VERSION 5.7 ;
  NOWIREEXTENSIONATPIN ON ;
  DIVIDERCHAR "/" ;
  BUSBITCHARS "[]" ;
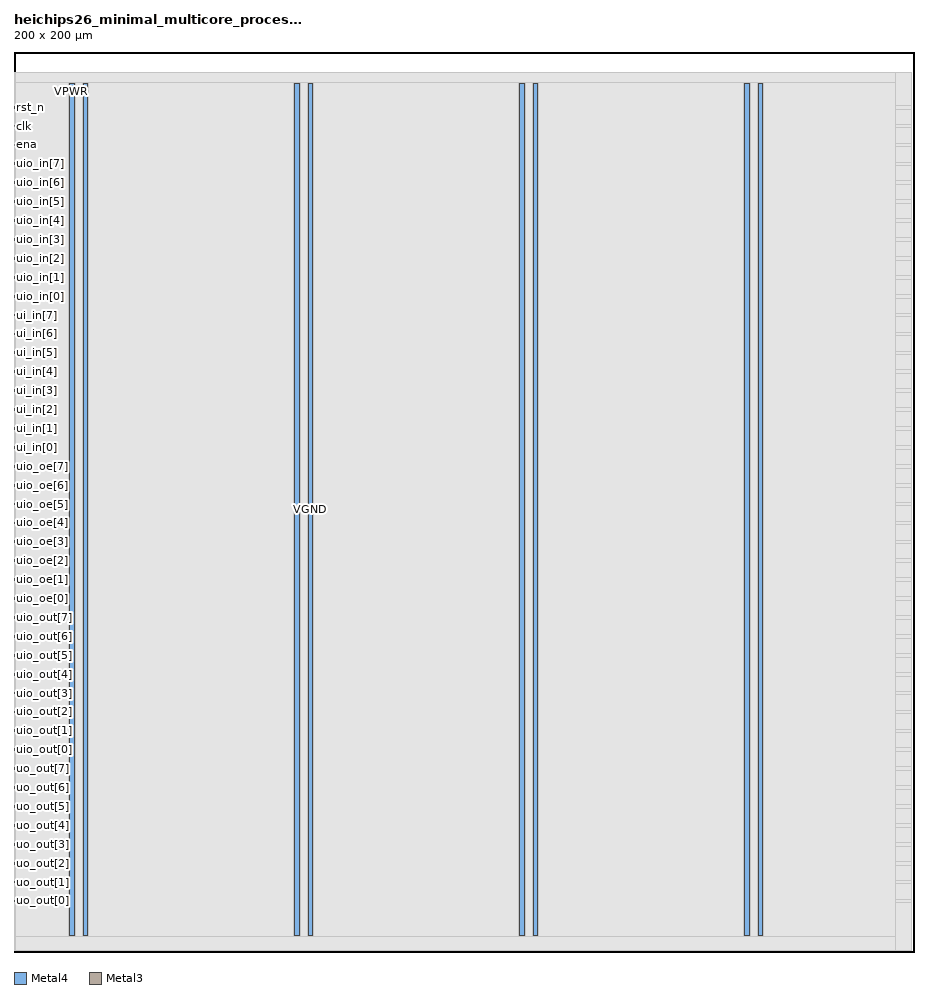
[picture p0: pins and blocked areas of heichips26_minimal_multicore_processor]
MACRO heichips26_minimal_multicore_processor
  CLASS BLOCK ;
  FOREIGN heichips26_minimal_multicore_processor ;
  ORIGIN 0.000 0.000 ;
  SIZE 200.000 BY 200.000 ;
  PIN VGND
    DIRECTION INOUT ;
    USE GROUND ;
    PORT
      LAYER Metal4 ;
        RECT 15.380 3.560 16.380 193.000 ;
    END
    PORT
      LAYER Metal4 ;
        RECT 65.380 3.560 66.380 193.000 ;
    END
    PORT
      LAYER Metal4 ;
        RECT 115.380 3.560 116.380 193.000 ;
    END
    PORT
      LAYER Metal4 ;
        RECT 165.380 3.560 166.380 193.000 ;
    END
  END VGND
  PIN VPWR
    DIRECTION INOUT ;
    USE POWER ;
    PORT
      LAYER Metal4 ;
        RECT 12.380 3.560 13.380 193.000 ;
    END
    PORT
      LAYER Metal4 ;
        RECT 62.380 3.560 63.380 193.000 ;
    END
    PORT
      LAYER Metal4 ;
        RECT 112.380 3.560 113.380 193.000 ;
    END
    PORT
      LAYER Metal4 ;
        RECT 162.380 3.560 163.380 193.000 ;
    END
  END VPWR
  PIN clk
    DIRECTION INPUT ;
    USE SIGNAL ;
    ANTENNAGATEAREA 0.725400 ;
    PORT
      LAYER Metal3 ;
        RECT 0.000 183.340 0.400 183.740 ;
    END
  END clk
  PIN ena
    DIRECTION INPUT ;
    USE SIGNAL ;
    PORT
      LAYER Metal3 ;
        RECT 0.000 179.140 0.400 179.540 ;
    END
  END ena
  PIN rst_n
    DIRECTION INPUT ;
    USE SIGNAL ;
    ANTENNAGATEAREA 0.180700 ;
    PORT
      LAYER Metal3 ;
        RECT 0.000 187.540 0.400 187.940 ;
    END
  END rst_n
  PIN ui_in[0]
    DIRECTION INPUT ;
    USE SIGNAL ;
    ANTENNAGATEAREA 0.180700 ;
    PORT
      LAYER Metal3 ;
        RECT 0.000 111.940 0.400 112.340 ;
    END
  END ui_in[0]
  PIN ui_in[1]
    DIRECTION INPUT ;
    USE SIGNAL ;
    ANTENNAGATEAREA 0.180700 ;
    PORT
      LAYER Metal3 ;
        RECT 0.000 116.140 0.400 116.540 ;
    END
  END ui_in[1]
  PIN ui_in[2]
    DIRECTION INPUT ;
    USE SIGNAL ;
    ANTENNAGATEAREA 0.180700 ;
    PORT
      LAYER Metal3 ;
        RECT 0.000 120.340 0.400 120.740 ;
    END
  END ui_in[2]
  PIN ui_in[3]
    DIRECTION INPUT ;
    USE SIGNAL ;
    ANTENNAGATEAREA 0.180700 ;
    PORT
      LAYER Metal3 ;
        RECT 0.000 124.540 0.400 124.940 ;
    END
  END ui_in[3]
  PIN ui_in[4]
    DIRECTION INPUT ;
    USE SIGNAL ;
    ANTENNAGATEAREA 0.180700 ;
    PORT
      LAYER Metal3 ;
        RECT 0.000 128.740 0.400 129.140 ;
    END
  END ui_in[4]
  PIN ui_in[5]
    DIRECTION INPUT ;
    USE SIGNAL ;
    ANTENNAGATEAREA 0.180700 ;
    PORT
      LAYER Metal3 ;
        RECT 0.000 132.940 0.400 133.340 ;
    END
  END ui_in[5]
  PIN ui_in[6]
    DIRECTION INPUT ;
    USE SIGNAL ;
    ANTENNAGATEAREA 0.180700 ;
    PORT
      LAYER Metal3 ;
        RECT 0.000 137.140 0.400 137.540 ;
    END
  END ui_in[6]
  PIN ui_in[7]
    DIRECTION INPUT ;
    USE SIGNAL ;
    ANTENNAGATEAREA 0.180700 ;
    PORT
      LAYER Metal3 ;
        RECT 0.000 141.340 0.400 141.740 ;
    END
  END ui_in[7]
  PIN uio_in[0]
    DIRECTION INPUT ;
    USE SIGNAL ;
    ANTENNAGATEAREA 0.180700 ;
    PORT
      LAYER Metal3 ;
        RECT 0.000 145.540 0.400 145.940 ;
    END
  END uio_in[0]
  PIN uio_in[1]
    DIRECTION INPUT ;
    USE SIGNAL ;
    ANTENNAGATEAREA 0.180700 ;
    PORT
      LAYER Metal3 ;
        RECT 0.000 149.740 0.400 150.140 ;
    END
  END uio_in[1]
  PIN uio_in[2]
    DIRECTION INPUT ;
    USE SIGNAL ;
    ANTENNAGATEAREA 0.180700 ;
    PORT
      LAYER Metal3 ;
        RECT 0.000 153.940 0.400 154.340 ;
    END
  END uio_in[2]
  PIN uio_in[3]
    DIRECTION INPUT ;
    USE SIGNAL ;
    ANTENNAGATEAREA 0.180700 ;
    PORT
      LAYER Metal3 ;
        RECT 0.000 158.140 0.400 158.540 ;
    END
  END uio_in[3]
  PIN uio_in[4]
    DIRECTION INPUT ;
    USE SIGNAL ;
    ANTENNAGATEAREA 0.180700 ;
    PORT
      LAYER Metal3 ;
        RECT 0.000 162.340 0.400 162.740 ;
    END
  END uio_in[4]
  PIN uio_in[5]
    DIRECTION INPUT ;
    USE SIGNAL ;
    ANTENNAGATEAREA 0.180700 ;
    PORT
      LAYER Metal3 ;
        RECT 0.000 166.540 0.400 166.940 ;
    END
  END uio_in[5]
  PIN uio_in[6]
    DIRECTION INPUT ;
    USE SIGNAL ;
    ANTENNAGATEAREA 0.180700 ;
    ANTENNADIFFAREA 2.015400 ;
    PORT
      LAYER Metal3 ;
        RECT 0.000 170.740 0.400 171.140 ;
    END
  END uio_in[6]
  PIN uio_in[7]
    DIRECTION INPUT ;
    USE SIGNAL ;
    ANTENNAGATEAREA 0.180700 ;
    ANTENNADIFFAREA 2.015400 ;
    PORT
      LAYER Metal3 ;
        RECT 0.000 174.940 0.400 175.340 ;
    END
  END uio_in[7]
  PIN uio_oe[0]
    DIRECTION OUTPUT ;
    USE SIGNAL ;
    ANTENNADIFFAREA 0.299200 ;
    PORT
      LAYER Metal3 ;
        RECT 0.000 78.340 0.400 78.740 ;
    END
  END uio_oe[0]
  PIN uio_oe[1]
    DIRECTION OUTPUT ;
    USE SIGNAL ;
    ANTENNADIFFAREA 0.299200 ;
    PORT
      LAYER Metal3 ;
        RECT 0.000 82.540 0.400 82.940 ;
    END
  END uio_oe[1]
  PIN uio_oe[2]
    DIRECTION OUTPUT ;
    USE SIGNAL ;
    ANTENNADIFFAREA 0.299200 ;
    PORT
      LAYER Metal3 ;
        RECT 0.000 86.740 0.400 87.140 ;
    END
  END uio_oe[2]
  PIN uio_oe[3]
    DIRECTION OUTPUT ;
    USE SIGNAL ;
    ANTENNADIFFAREA 0.299200 ;
    PORT
      LAYER Metal3 ;
        RECT 0.000 90.940 0.400 91.340 ;
    END
  END uio_oe[3]
  PIN uio_oe[4]
    DIRECTION OUTPUT ;
    USE SIGNAL ;
    ANTENNADIFFAREA 0.299200 ;
    PORT
      LAYER Metal3 ;
        RECT 0.000 95.140 0.400 95.540 ;
    END
  END uio_oe[4]
  PIN uio_oe[5]
    DIRECTION OUTPUT ;
    USE SIGNAL ;
    ANTENNADIFFAREA 0.299200 ;
    PORT
      LAYER Metal3 ;
        RECT 0.000 99.340 0.400 99.740 ;
    END
  END uio_oe[5]
  PIN uio_oe[6]
    DIRECTION OUTPUT ;
    USE SIGNAL ;
    ANTENNADIFFAREA 0.299200 ;
    PORT
      LAYER Metal3 ;
        RECT 0.000 103.540 0.400 103.940 ;
    END
  END uio_oe[6]
  PIN uio_oe[7]
    DIRECTION OUTPUT ;
    USE SIGNAL ;
    ANTENNADIFFAREA 0.299200 ;
    PORT
      LAYER Metal3 ;
        RECT 0.000 107.740 0.400 108.140 ;
    END
  END uio_oe[7]
  PIN uio_out[0]
    DIRECTION OUTPUT ;
    USE SIGNAL ;
    ANTENNADIFFAREA 0.299200 ;
    PORT
      LAYER Metal3 ;
        RECT 0.000 44.740 0.400 45.140 ;
    END
  END uio_out[0]
  PIN uio_out[1]
    DIRECTION OUTPUT ;
    USE SIGNAL ;
    ANTENNADIFFAREA 0.299200 ;
    PORT
      LAYER Metal3 ;
        RECT 0.000 48.940 0.400 49.340 ;
    END
  END uio_out[1]
  PIN uio_out[2]
    DIRECTION OUTPUT ;
    USE SIGNAL ;
    ANTENNADIFFAREA 0.299200 ;
    PORT
      LAYER Metal3 ;
        RECT 0.000 53.140 0.400 53.540 ;
    END
  END uio_out[2]
  PIN uio_out[3]
    DIRECTION OUTPUT ;
    USE SIGNAL ;
    ANTENNADIFFAREA 0.299200 ;
    PORT
      LAYER Metal3 ;
        RECT 0.000 57.340 0.400 57.740 ;
    END
  END uio_out[3]
  PIN uio_out[4]
    DIRECTION OUTPUT ;
    USE SIGNAL ;
    ANTENNADIFFAREA 0.299200 ;
    PORT
      LAYER Metal3 ;
        RECT 0.000 61.540 0.400 61.940 ;
    END
  END uio_out[4]
  PIN uio_out[5]
    DIRECTION OUTPUT ;
    USE SIGNAL ;
    ANTENNADIFFAREA 0.299200 ;
    PORT
      LAYER Metal3 ;
        RECT 0.000 65.740 0.400 66.140 ;
    END
  END uio_out[5]
  PIN uio_out[6]
    DIRECTION OUTPUT ;
    USE SIGNAL ;
    ANTENNADIFFAREA 0.299200 ;
    PORT
      LAYER Metal3 ;
        RECT 0.000 69.940 0.400 70.340 ;
    END
  END uio_out[6]
  PIN uio_out[7]
    DIRECTION OUTPUT ;
    USE SIGNAL ;
    ANTENNADIFFAREA 0.299200 ;
    PORT
      LAYER Metal3 ;
        RECT 0.000 74.140 0.400 74.540 ;
    END
  END uio_out[7]
  PIN uo_out[0]
    DIRECTION OUTPUT ;
    USE SIGNAL ;
    ANTENNADIFFAREA 0.708600 ;
    PORT
      LAYER Metal3 ;
        RECT 0.000 11.140 0.400 11.540 ;
    END
  END uo_out[0]
  PIN uo_out[1]
    DIRECTION OUTPUT ;
    USE SIGNAL ;
    ANTENNADIFFAREA 0.708600 ;
    PORT
      LAYER Metal3 ;
        RECT 0.000 15.340 0.400 15.740 ;
    END
  END uo_out[1]
  PIN uo_out[2]
    DIRECTION OUTPUT ;
    USE SIGNAL ;
    ANTENNADIFFAREA 0.708600 ;
    PORT
      LAYER Metal3 ;
        RECT 0.000 19.540 0.400 19.940 ;
    END
  END uo_out[2]
  PIN uo_out[3]
    DIRECTION OUTPUT ;
    USE SIGNAL ;
    ANTENNADIFFAREA 0.708600 ;
    PORT
      LAYER Metal3 ;
        RECT 0.000 23.740 0.400 24.140 ;
    END
  END uo_out[3]
  PIN uo_out[4]
    DIRECTION OUTPUT ;
    USE SIGNAL ;
    ANTENNADIFFAREA 0.708600 ;
    PORT
      LAYER Metal3 ;
        RECT 0.000 27.940 0.400 28.340 ;
    END
  END uo_out[4]
  PIN uo_out[5]
    DIRECTION OUTPUT ;
    USE SIGNAL ;
    ANTENNADIFFAREA 0.708600 ;
    PORT
      LAYER Metal3 ;
        RECT 0.000 32.140 0.400 32.540 ;
    END
  END uo_out[5]
  PIN uo_out[6]
    DIRECTION OUTPUT ;
    USE SIGNAL ;
    ANTENNADIFFAREA 0.708600 ;
    PORT
      LAYER Metal3 ;
        RECT 0.000 36.340 0.400 36.740 ;
    END
  END uo_out[6]
  PIN uo_out[7]
    DIRECTION OUTPUT ;
    USE SIGNAL ;
    ANTENNADIFFAREA 0.708600 ;
    PORT
      LAYER Metal3 ;
        RECT 0.000 40.540 0.400 40.940 ;
    END
  END uo_out[7]
  OBS
      LAYER GatPoly ;
        RECT 2.880 3.630 196.800 192.930 ;
      LAYER Metal1 ;
        RECT 2.880 3.560 196.800 193.000 ;
      LAYER Metal2 ;
        RECT 0.375 0.275 199.305 195.445 ;
      LAYER Metal3 ;
        RECT 0.100 188.150 199.345 195.405 ;
        RECT 0.610 187.330 199.345 188.150 ;
        RECT 0.100 183.950 199.345 187.330 ;
        RECT 0.610 183.130 199.345 183.950 ;
        RECT 0.100 179.750 199.345 183.130 ;
        RECT 0.610 178.930 199.345 179.750 ;
        RECT 0.100 175.550 199.345 178.930 ;
        RECT 0.610 174.730 199.345 175.550 ;
        RECT 0.100 171.350 199.345 174.730 ;
        RECT 0.610 170.530 199.345 171.350 ;
        RECT 0.100 167.150 199.345 170.530 ;
        RECT 0.610 166.330 199.345 167.150 ;
        RECT 0.100 162.950 199.345 166.330 ;
        RECT 0.610 162.130 199.345 162.950 ;
        RECT 0.100 158.750 199.345 162.130 ;
        RECT 0.610 157.930 199.345 158.750 ;
        RECT 0.100 154.550 199.345 157.930 ;
        RECT 0.610 153.730 199.345 154.550 ;
        RECT 0.100 150.350 199.345 153.730 ;
        RECT 0.610 149.530 199.345 150.350 ;
        RECT 0.100 146.150 199.345 149.530 ;
        RECT 0.610 145.330 199.345 146.150 ;
        RECT 0.100 141.950 199.345 145.330 ;
        RECT 0.610 141.130 199.345 141.950 ;
        RECT 0.100 137.750 199.345 141.130 ;
        RECT 0.610 136.930 199.345 137.750 ;
        RECT 0.100 133.550 199.345 136.930 ;
        RECT 0.610 132.730 199.345 133.550 ;
        RECT 0.100 129.350 199.345 132.730 ;
        RECT 0.610 128.530 199.345 129.350 ;
        RECT 0.100 125.150 199.345 128.530 ;
        RECT 0.610 124.330 199.345 125.150 ;
        RECT 0.100 120.950 199.345 124.330 ;
        RECT 0.610 120.130 199.345 120.950 ;
        RECT 0.100 116.750 199.345 120.130 ;
        RECT 0.610 115.930 199.345 116.750 ;
        RECT 0.100 112.550 199.345 115.930 ;
        RECT 0.610 111.730 199.345 112.550 ;
        RECT 0.100 108.350 199.345 111.730 ;
        RECT 0.610 107.530 199.345 108.350 ;
        RECT 0.100 104.150 199.345 107.530 ;
        RECT 0.610 103.330 199.345 104.150 ;
        RECT 0.100 99.950 199.345 103.330 ;
        RECT 0.610 99.130 199.345 99.950 ;
        RECT 0.100 95.750 199.345 99.130 ;
        RECT 0.610 94.930 199.345 95.750 ;
        RECT 0.100 91.550 199.345 94.930 ;
        RECT 0.610 90.730 199.345 91.550 ;
        RECT 0.100 87.350 199.345 90.730 ;
        RECT 0.610 86.530 199.345 87.350 ;
        RECT 0.100 83.150 199.345 86.530 ;
        RECT 0.610 82.330 199.345 83.150 ;
        RECT 0.100 78.950 199.345 82.330 ;
        RECT 0.610 78.130 199.345 78.950 ;
        RECT 0.100 74.750 199.345 78.130 ;
        RECT 0.610 73.930 199.345 74.750 ;
        RECT 0.100 70.550 199.345 73.930 ;
        RECT 0.610 69.730 199.345 70.550 ;
        RECT 0.100 66.350 199.345 69.730 ;
        RECT 0.610 65.530 199.345 66.350 ;
        RECT 0.100 62.150 199.345 65.530 ;
        RECT 0.610 61.330 199.345 62.150 ;
        RECT 0.100 57.950 199.345 61.330 ;
        RECT 0.610 57.130 199.345 57.950 ;
        RECT 0.100 53.750 199.345 57.130 ;
        RECT 0.610 52.930 199.345 53.750 ;
        RECT 0.100 49.550 199.345 52.930 ;
        RECT 0.610 48.730 199.345 49.550 ;
        RECT 0.100 45.350 199.345 48.730 ;
        RECT 0.610 44.530 199.345 45.350 ;
        RECT 0.100 41.150 199.345 44.530 ;
        RECT 0.610 40.330 199.345 41.150 ;
        RECT 0.100 36.950 199.345 40.330 ;
        RECT 0.610 36.130 199.345 36.950 ;
        RECT 0.100 32.750 199.345 36.130 ;
        RECT 0.610 31.930 199.345 32.750 ;
        RECT 0.100 28.550 199.345 31.930 ;
        RECT 0.610 27.730 199.345 28.550 ;
        RECT 0.100 24.350 199.345 27.730 ;
        RECT 0.610 23.530 199.345 24.350 ;
        RECT 0.100 20.150 199.345 23.530 ;
        RECT 0.610 19.330 199.345 20.150 ;
        RECT 0.100 15.950 199.345 19.330 ;
        RECT 0.610 15.130 199.345 15.950 ;
        RECT 0.100 11.750 199.345 15.130 ;
        RECT 0.610 10.930 199.345 11.750 ;
        RECT 0.100 0.315 199.345 10.930 ;
      LAYER Metal4 ;
        RECT 0.380 193.210 195.940 195.445 ;
        RECT 0.380 3.350 12.170 193.210 ;
        RECT 13.590 3.350 15.170 193.210 ;
        RECT 16.590 3.350 62.170 193.210 ;
        RECT 63.590 3.350 65.170 193.210 ;
        RECT 66.590 3.350 112.170 193.210 ;
        RECT 113.590 3.350 115.170 193.210 ;
        RECT 116.590 3.350 162.170 193.210 ;
        RECT 163.590 3.350 165.170 193.210 ;
        RECT 166.590 3.350 195.940 193.210 ;
        RECT 0.380 0.275 195.940 3.350 ;
  END
END heichips26_minimal_multicore_processor
END LIBRARY

